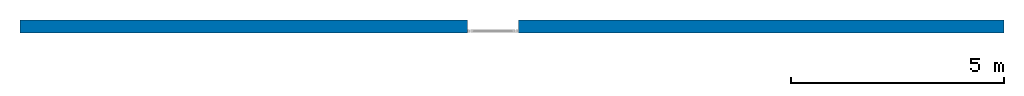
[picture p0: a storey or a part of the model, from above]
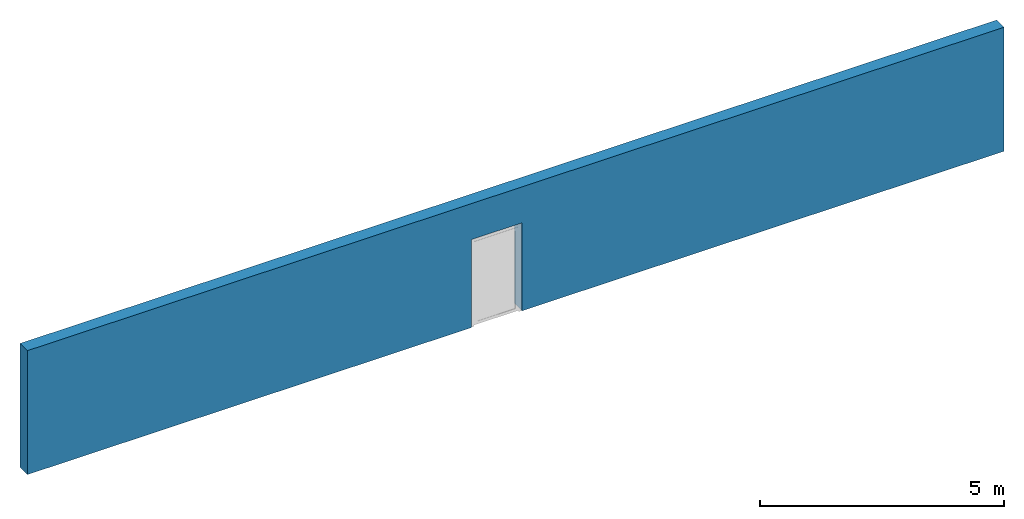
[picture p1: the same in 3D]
Properties of the parts of a building model (IFC2X3)

# File
Description: ViewDefinition [CoordinationView_V2.0]
File name: 0001
Time: 2021-05-04T09:21:18
Written by: The EXPRESS Data Manager Version 5.02.0100.07 : 28 Aug 2013
Made in: 20170223_1515(x64) - Exporter 18.0.0.420 - Alternate UI 18.0.0.420
Comment: STEP Physical File produced by: The EXPRESS Data Manager Version 5.02.0100.07 : 28 Aug 2013 * Module: EDMstepFileFactory/EDMstandAlone * Creation date: Tue May 04 09:21:18 2021 * Host: RISO-PC * Database: C:\Users\MARTIN~1\AppData\Local\Temp\{799349A5-FBFF-442B-9531-D82C7B22BAA7}\ifc * Database version: 5507 * Database creation date: Tue May 04 09:21:17 2021 * Schema: IFC2X3 * Model: DataRepository.ifc * Model creation date: Tue May 04 09:21:17 2021 * Header model: DataRepository.ifc_HeaderModel * Header model creation date: Tue May 04 09:21:17 2021 * EDMuser: sdai-user * EDMgroup: sdai-group * License ID and type: 5605 : Permanent license. Expiry date: * EDMstepFileFactory options: 020000

# IfcProject, 0001
LongName: Nome; Phase: Stato

# IfcSite, Default
RefLatitude: 41, 47, 59, 997253; RefLongitude: 12, 36, 0, 1373; RefElevation: 0 m

# IfcBuilding
Pset_BuildingCommon - NumberOfStoreys: 1

# IfcBuildingStorey, 0 - Piano Terra
LongName: 0 - Piano Terra; Elevation: 0 m

# IfcWallStandardCase: Muro di base:Generico - 30 cm, Muro di base:Generico - 30 cm:133331
In: 0 - Piano Terra
Type - PredefinedType: STANDARD; Material: Default - Muro 0.3 m
Pset_WallCommon - Reference: Generico - 30 cm; LoadBearing: no; ExtendToStructure: no; IsExternal: yes

# IfcWindow: BIM_AluK_D77_1 anta, BIM_AluK_D77_1 anta:BIM_AluK_D77_1 anta:136343
In: 0 - Piano Terra
Type - ParameterTakesPrecedence: no; Sizeable: no; Material: Aluk (IT), Vetro
OverallHeight: 2.2 m; OverallWidth: 1.2 m
Pset_WindowCommon - IsExternal: yes; Reference: BIM_AluK_D77_1 anta
Pset_ManufacturerTypeInformation - Manufacturer: Aluk (IT)
